VERSION 5.7 ;
  NOWIREEXTENSIONATPIN ON ;
  DIVIDERCHAR "/" ;
  BUSBITCHARS "[]" ;
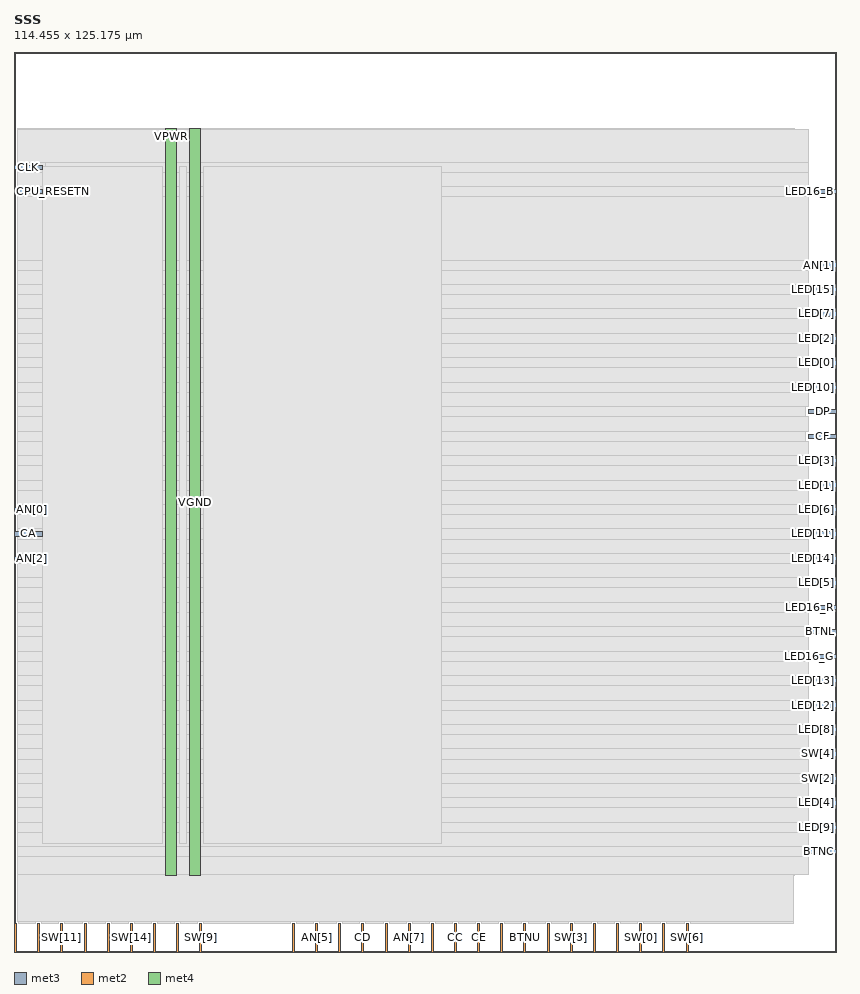
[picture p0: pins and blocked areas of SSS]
MACRO SSS
  CLASS BLOCK ;
  FOREIGN SSS ;
  ORIGIN 0.000 0.000 ;
  SIZE 114.455 BY 125.175 ;
  PIN AN[0]
    DIRECTION OUTPUT ;
    USE SIGNAL ;
    ANTENNADIFFAREA 0.445500 ;
    PORT
      LAYER met3 ;
        RECT 0.000 61.240 4.000 61.840 ;
    END
  END AN[0]
  PIN AN[1]
    DIRECTION OUTPUT ;
    USE SIGNAL ;
    ANTENNADIFFAREA 0.445500 ;
    PORT
      LAYER met3 ;
        RECT 110.455 95.240 114.455 95.840 ;
    END
  END AN[1]
  PIN AN[2]
    DIRECTION OUTPUT ;
    USE SIGNAL ;
    ANTENNADIFFAREA 0.445500 ;
    PORT
      LAYER met3 ;
        RECT 0.000 54.440 4.000 55.040 ;
    END
  END AN[2]
  PIN AN[3]
    DIRECTION OUTPUT ;
    USE SIGNAL ;
    ANTENNADIFFAREA 0.445500 ;
    PORT
      LAYER met2 ;
        RECT 67.710 0.000 67.990 4.000 ;
    END
  END AN[3]
  PIN AN[4]
    DIRECTION OUTPUT ;
    USE SIGNAL ;
    ANTENNADIFFAREA 0.445500 ;
    PORT
      LAYER met2 ;
        RECT 38.730 0.000 39.010 4.000 ;
    END
  END AN[4]
  PIN AN[5]
    DIRECTION OUTPUT ;
    USE SIGNAL ;
    ANTENNADIFFAREA 0.445500 ;
    PORT
      LAYER met2 ;
        RECT 41.950 0.000 42.230 4.000 ;
    END
  END AN[5]
  PIN AN[6]
    DIRECTION OUTPUT ;
    USE SIGNAL ;
    ANTENNADIFFAREA 0.445500 ;
    PORT
      LAYER met2 ;
        RECT 45.170 0.000 45.450 4.000 ;
    END
  END AN[6]
  PIN AN[7]
    DIRECTION OUTPUT ;
    USE SIGNAL ;
    ANTENNADIFFAREA 0.445500 ;
    PORT
      LAYER met2 ;
        RECT 54.830 0.000 55.110 4.000 ;
    END
  END AN[7]
  PIN BTNC
    DIRECTION INPUT ;
    USE SIGNAL ;
    ANTENNAGATEAREA 0.126000 ;
    PORT
      LAYER met3 ;
        RECT 110.455 13.640 114.455 14.240 ;
    END
  END BTNC
  PIN BTND
    DIRECTION INPUT ;
    USE SIGNAL ;
    PORT
      LAYER met2 ;
        RECT 0.090 0.000 0.370 4.000 ;
    END
  END BTND
  PIN BTNL
    DIRECTION INPUT ;
    USE SIGNAL ;
    ANTENNAGATEAREA 0.196500 ;
    PORT
      LAYER met3 ;
        RECT 110.455 44.240 114.455 44.840 ;
    END
  END BTNL
  PIN BTNR
    DIRECTION INPUT ;
    USE SIGNAL ;
    ANTENNAGATEAREA 0.196500 ;
    PORT
      LAYER met2 ;
        RECT 74.150 0.000 74.430 4.000 ;
    END
  END BTNR
  PIN BTNU
    DIRECTION INPUT ;
    USE SIGNAL ;
    ANTENNAGATEAREA 0.196500 ;
    PORT
      LAYER met2 ;
        RECT 70.930 0.000 71.210 4.000 ;
    END
  END BTNU
  PIN CA
    DIRECTION OUTPUT ;
    USE SIGNAL ;
    ANTENNADIFFAREA 0.445500 ;
    PORT
      LAYER met3 ;
        RECT 0.000 57.840 4.000 58.440 ;
    END
  END CA
  PIN CB
    DIRECTION OUTPUT ;
    USE SIGNAL ;
    ANTENNADIFFAREA 0.445500 ;
    PORT
      LAYER met2 ;
        RECT 58.050 0.000 58.330 4.000 ;
    END
  END CB
  PIN CC
    DIRECTION OUTPUT ;
    USE SIGNAL ;
    ANTENNADIFFAREA 0.445500 ;
    PORT
      LAYER met2 ;
        RECT 61.270 0.000 61.550 4.000 ;
    END
  END CC
  PIN CD
    DIRECTION OUTPUT ;
    USE SIGNAL ;
    ANTENNADIFFAREA 0.445500 ;
    PORT
      LAYER met2 ;
        RECT 48.390 0.000 48.670 4.000 ;
    END
  END CD
  PIN CE
    DIRECTION OUTPUT ;
    USE SIGNAL ;
    ANTENNADIFFAREA 0.445500 ;
    PORT
      LAYER met2 ;
        RECT 64.490 0.000 64.770 4.000 ;
    END
  END CE
  PIN CF
    DIRECTION OUTPUT ;
    USE SIGNAL ;
    ANTENNADIFFAREA 0.445500 ;
    PORT
      LAYER met3 ;
        RECT 110.455 71.440 114.455 72.040 ;
    END
  END CF
  PIN CG
    DIRECTION OUTPUT ;
    USE SIGNAL ;
    ANTENNADIFFAREA 0.445500 ;
    PORT
      LAYER met2 ;
        RECT 51.610 0.000 51.890 4.000 ;
    END
  END CG
  PIN CLK
    DIRECTION INPUT ;
    USE SIGNAL ;
    ANTENNAGATEAREA 0.852000 ;
    PORT
      LAYER met3 ;
        RECT 0.000 108.840 4.000 109.440 ;
    END
  END CLK
  PIN CPU_RESETN
    DIRECTION INPUT ;
    USE SIGNAL ;
    ANTENNAGATEAREA 0.196500 ;
    PORT
      LAYER met3 ;
        RECT 0.000 105.440 4.000 106.040 ;
    END
  END CPU_RESETN
  PIN DP
    DIRECTION OUTPUT ;
    USE SIGNAL ;
    PORT
      LAYER met3 ;
        RECT 110.455 74.840 114.455 75.440 ;
    END
  END DP
  PIN LED16_B
    DIRECTION OUTPUT ;
    USE SIGNAL ;
    PORT
      LAYER met3 ;
        RECT 110.455 105.440 114.455 106.040 ;
    END
  END LED16_B
  PIN LED16_G
    DIRECTION OUTPUT ;
    USE SIGNAL ;
    ANTENNADIFFAREA 0.445500 ;
    PORT
      LAYER met3 ;
        RECT 110.455 40.840 114.455 41.440 ;
    END
  END LED16_G
  PIN LED16_R
    DIRECTION OUTPUT ;
    USE SIGNAL ;
    ANTENNADIFFAREA 0.445500 ;
    PORT
      LAYER met3 ;
        RECT 110.455 47.640 114.455 48.240 ;
    END
  END LED16_R
  PIN LED[0]
    DIRECTION OUTPUT ;
    USE SIGNAL ;
    ANTENNADIFFAREA 0.445500 ;
    PORT
      LAYER met3 ;
        RECT 110.455 81.640 114.455 82.240 ;
    END
  END LED[0]
  PIN LED[10]
    DIRECTION OUTPUT ;
    USE SIGNAL ;
    ANTENNADIFFAREA 0.445500 ;
    PORT
      LAYER met3 ;
        RECT 110.455 78.240 114.455 78.840 ;
    END
  END LED[10]
  PIN LED[11]
    DIRECTION OUTPUT ;
    USE SIGNAL ;
    ANTENNADIFFAREA 0.445500 ;
    PORT
      LAYER met3 ;
        RECT 110.455 57.840 114.455 58.440 ;
    END
  END LED[11]
  PIN LED[12]
    DIRECTION OUTPUT ;
    USE SIGNAL ;
    ANTENNADIFFAREA 0.445500 ;
    PORT
      LAYER met3 ;
        RECT 110.455 34.040 114.455 34.640 ;
    END
  END LED[12]
  PIN LED[13]
    DIRECTION OUTPUT ;
    USE SIGNAL ;
    ANTENNADIFFAREA 0.445500 ;
    PORT
      LAYER met3 ;
        RECT 110.455 37.440 114.455 38.040 ;
    END
  END LED[13]
  PIN LED[14]
    DIRECTION OUTPUT ;
    USE SIGNAL ;
    ANTENNADIFFAREA 0.445500 ;
    PORT
      LAYER met3 ;
        RECT 110.455 54.440 114.455 55.040 ;
    END
  END LED[14]
  PIN LED[15]
    DIRECTION OUTPUT ;
    USE SIGNAL ;
    ANTENNADIFFAREA 0.445500 ;
    PORT
      LAYER met3 ;
        RECT 110.455 91.840 114.455 92.440 ;
    END
  END LED[15]
  PIN LED[1]
    DIRECTION OUTPUT ;
    USE SIGNAL ;
    ANTENNADIFFAREA 0.445500 ;
    PORT
      LAYER met3 ;
        RECT 110.455 64.640 114.455 65.240 ;
    END
  END LED[1]
  PIN LED[2]
    DIRECTION OUTPUT ;
    USE SIGNAL ;
    ANTENNADIFFAREA 0.445500 ;
    PORT
      LAYER met3 ;
        RECT 110.455 85.040 114.455 85.640 ;
    END
  END LED[2]
  PIN LED[3]
    DIRECTION OUTPUT ;
    USE SIGNAL ;
    ANTENNADIFFAREA 0.445500 ;
    PORT
      LAYER met3 ;
        RECT 110.455 68.040 114.455 68.640 ;
    END
  END LED[3]
  PIN LED[4]
    DIRECTION OUTPUT ;
    USE SIGNAL ;
    ANTENNADIFFAREA 0.445500 ;
    PORT
      LAYER met3 ;
        RECT 110.455 20.440 114.455 21.040 ;
    END
  END LED[4]
  PIN LED[5]
    DIRECTION OUTPUT ;
    USE SIGNAL ;
    ANTENNADIFFAREA 0.445500 ;
    PORT
      LAYER met3 ;
        RECT 110.455 51.040 114.455 51.640 ;
    END
  END LED[5]
  PIN LED[6]
    DIRECTION OUTPUT ;
    USE SIGNAL ;
    ANTENNADIFFAREA 0.445500 ;
    PORT
      LAYER met3 ;
        RECT 110.455 61.240 114.455 61.840 ;
    END
  END LED[6]
  PIN LED[7]
    DIRECTION OUTPUT ;
    USE SIGNAL ;
    ANTENNADIFFAREA 0.445500 ;
    PORT
      LAYER met3 ;
        RECT 110.455 88.440 114.455 89.040 ;
    END
  END LED[7]
  PIN LED[8]
    DIRECTION OUTPUT ;
    USE SIGNAL ;
    ANTENNADIFFAREA 0.445500 ;
    PORT
      LAYER met3 ;
        RECT 110.455 30.640 114.455 31.240 ;
    END
  END LED[8]
  PIN LED[9]
    DIRECTION OUTPUT ;
    USE SIGNAL ;
    ANTENNADIFFAREA 0.445500 ;
    PORT
      LAYER met3 ;
        RECT 110.455 17.040 114.455 17.640 ;
    END
  END LED[9]
  PIN SW[0]
    DIRECTION INPUT ;
    USE SIGNAL ;
    ANTENNAGATEAREA 0.196500 ;
    PORT
      LAYER met2 ;
        RECT 87.030 0.000 87.310 4.000 ;
    END
  END SW[0]
  PIN SW[10]
    DIRECTION INPUT ;
    USE SIGNAL ;
    PORT
      LAYER met2 ;
        RECT 3.310 0.000 3.590 4.000 ;
    END
  END SW[10]
  PIN SW[11]
    DIRECTION INPUT ;
    USE SIGNAL ;
    PORT
      LAYER met2 ;
        RECT 6.530 0.000 6.810 4.000 ;
    END
  END SW[11]
  PIN SW[12]
    DIRECTION INPUT ;
    USE SIGNAL ;
    PORT
      LAYER met2 ;
        RECT 9.750 0.000 10.030 4.000 ;
    END
  END SW[12]
  PIN SW[13]
    DIRECTION INPUT ;
    USE SIGNAL ;
    PORT
      LAYER met2 ;
        RECT 12.970 0.000 13.250 4.000 ;
    END
  END SW[13]
  PIN SW[14]
    DIRECTION INPUT ;
    USE SIGNAL ;
    PORT
      LAYER met2 ;
        RECT 16.190 0.000 16.470 4.000 ;
    END
  END SW[14]
  PIN SW[15]
    DIRECTION INPUT ;
    USE SIGNAL ;
    PORT
      LAYER met2 ;
        RECT 19.410 0.000 19.690 4.000 ;
    END
  END SW[15]
  PIN SW[1]
    DIRECTION INPUT ;
    USE SIGNAL ;
    ANTENNAGATEAREA 0.196500 ;
    PORT
      LAYER met2 ;
        RECT 90.250 0.000 90.530 4.000 ;
    END
  END SW[1]
  PIN SW[2]
    DIRECTION INPUT ;
    USE SIGNAL ;
    ANTENNAGATEAREA 0.196500 ;
    PORT
      LAYER met3 ;
        RECT 110.455 23.840 114.455 24.440 ;
    END
  END SW[2]
  PIN SW[3]
    DIRECTION INPUT ;
    USE SIGNAL ;
    ANTENNAGATEAREA 0.196500 ;
    PORT
      LAYER met2 ;
        RECT 77.370 0.000 77.650 4.000 ;
    END
  END SW[3]
  PIN SW[4]
    DIRECTION INPUT ;
    USE SIGNAL ;
    ANTENNAGATEAREA 0.196500 ;
    PORT
      LAYER met3 ;
        RECT 110.455 27.240 114.455 27.840 ;
    END
  END SW[4]
  PIN SW[5]
    DIRECTION INPUT ;
    USE SIGNAL ;
    ANTENNAGATEAREA 0.196500 ;
    PORT
      LAYER met2 ;
        RECT 80.590 0.000 80.870 4.000 ;
    END
  END SW[5]
  PIN SW[6]
    DIRECTION INPUT ;
    USE SIGNAL ;
    ANTENNAGATEAREA 0.196500 ;
    PORT
      LAYER met2 ;
        RECT 93.470 0.000 93.750 4.000 ;
    END
  END SW[6]
  PIN SW[7]
    DIRECTION INPUT ;
    USE SIGNAL ;
    ANTENNAGATEAREA 0.196500 ;
    PORT
      LAYER met2 ;
        RECT 83.810 0.000 84.090 4.000 ;
    END
  END SW[7]
  PIN SW[8]
    DIRECTION INPUT ;
    USE SIGNAL ;
    PORT
      LAYER met2 ;
        RECT 22.630 0.000 22.910 4.000 ;
    END
  END SW[8]
  PIN SW[9]
    DIRECTION INPUT ;
    USE SIGNAL ;
    PORT
      LAYER met2 ;
        RECT 25.850 0.000 26.130 4.000 ;
    END
  END SW[9]
  PIN VGND
    DIRECTION INOUT ;
    USE GROUND ;
    PORT
      LAYER met4 ;
        RECT 24.340 10.640 25.940 114.480 ;
    END
  END VGND
  PIN VPWR
    DIRECTION INOUT ;
    USE POWER ;
    PORT
      LAYER met4 ;
        RECT 21.040 10.640 22.640 114.480 ;
    END
  END VPWR
  OBS
      LAYER nwell ;
        RECT 5.330 10.795 108.750 114.325 ;
      LAYER li1 ;
        RECT 5.520 10.795 108.560 114.325 ;
      LAYER met1 ;
        RECT 0.530 10.640 108.560 114.480 ;
      LAYER met2 ;
        RECT 0.550 4.280 108.460 114.425 ;
        RECT 0.650 4.000 3.030 4.280 ;
        RECT 3.870 4.000 6.250 4.280 ;
        RECT 7.090 4.000 9.470 4.280 ;
        RECT 10.310 4.000 12.690 4.280 ;
        RECT 13.530 4.000 15.910 4.280 ;
        RECT 16.750 4.000 19.130 4.280 ;
        RECT 19.970 4.000 22.350 4.280 ;
        RECT 23.190 4.000 25.570 4.280 ;
        RECT 26.410 4.000 38.450 4.280 ;
        RECT 39.290 4.000 41.670 4.280 ;
        RECT 42.510 4.000 44.890 4.280 ;
        RECT 45.730 4.000 48.110 4.280 ;
        RECT 48.950 4.000 51.330 4.280 ;
        RECT 52.170 4.000 54.550 4.280 ;
        RECT 55.390 4.000 57.770 4.280 ;
        RECT 58.610 4.000 60.990 4.280 ;
        RECT 61.830 4.000 64.210 4.280 ;
        RECT 65.050 4.000 67.430 4.280 ;
        RECT 68.270 4.000 70.650 4.280 ;
        RECT 71.490 4.000 73.870 4.280 ;
        RECT 74.710 4.000 77.090 4.280 ;
        RECT 77.930 4.000 80.310 4.280 ;
        RECT 81.150 4.000 83.530 4.280 ;
        RECT 84.370 4.000 86.750 4.280 ;
        RECT 87.590 4.000 89.970 4.280 ;
        RECT 90.810 4.000 93.190 4.280 ;
        RECT 94.030 4.000 108.460 4.280 ;
      LAYER met3 ;
        RECT 0.525 109.840 110.455 114.405 ;
        RECT 4.400 108.440 110.455 109.840 ;
        RECT 0.525 106.440 110.455 108.440 ;
        RECT 4.400 105.040 110.055 106.440 ;
        RECT 0.525 96.240 110.455 105.040 ;
        RECT 0.525 94.840 110.055 96.240 ;
        RECT 0.525 92.840 110.455 94.840 ;
        RECT 0.525 91.440 110.055 92.840 ;
        RECT 0.525 89.440 110.455 91.440 ;
        RECT 0.525 88.040 110.055 89.440 ;
        RECT 0.525 86.040 110.455 88.040 ;
        RECT 0.525 84.640 110.055 86.040 ;
        RECT 0.525 82.640 110.455 84.640 ;
        RECT 0.525 81.240 110.055 82.640 ;
        RECT 0.525 79.240 110.455 81.240 ;
        RECT 0.525 77.840 110.055 79.240 ;
        RECT 0.525 75.840 110.455 77.840 ;
        RECT 0.525 74.440 110.055 75.840 ;
        RECT 0.525 72.440 110.455 74.440 ;
        RECT 0.525 71.040 110.055 72.440 ;
        RECT 0.525 69.040 110.455 71.040 ;
        RECT 0.525 67.640 110.055 69.040 ;
        RECT 0.525 65.640 110.455 67.640 ;
        RECT 0.525 64.240 110.055 65.640 ;
        RECT 0.525 62.240 110.455 64.240 ;
        RECT 4.400 60.840 110.055 62.240 ;
        RECT 0.525 58.840 110.455 60.840 ;
        RECT 4.400 57.440 110.055 58.840 ;
        RECT 0.525 55.440 110.455 57.440 ;
        RECT 4.400 54.040 110.055 55.440 ;
        RECT 0.525 52.040 110.455 54.040 ;
        RECT 0.525 50.640 110.055 52.040 ;
        RECT 0.525 48.640 110.455 50.640 ;
        RECT 0.525 47.240 110.055 48.640 ;
        RECT 0.525 45.240 110.455 47.240 ;
        RECT 0.525 43.840 110.055 45.240 ;
        RECT 0.525 41.840 110.455 43.840 ;
        RECT 0.525 40.440 110.055 41.840 ;
        RECT 0.525 38.440 110.455 40.440 ;
        RECT 0.525 37.040 110.055 38.440 ;
        RECT 0.525 35.040 110.455 37.040 ;
        RECT 0.525 33.640 110.055 35.040 ;
        RECT 0.525 31.640 110.455 33.640 ;
        RECT 0.525 30.240 110.055 31.640 ;
        RECT 0.525 28.240 110.455 30.240 ;
        RECT 0.525 26.840 110.055 28.240 ;
        RECT 0.525 24.840 110.455 26.840 ;
        RECT 0.525 23.440 110.055 24.840 ;
        RECT 0.525 21.440 110.455 23.440 ;
        RECT 0.525 20.040 110.055 21.440 ;
        RECT 0.525 18.040 110.455 20.040 ;
        RECT 0.525 16.640 110.055 18.040 ;
        RECT 0.525 14.640 110.455 16.640 ;
        RECT 0.525 13.240 110.055 14.640 ;
        RECT 0.525 10.715 110.455 13.240 ;
      LAYER met4 ;
        RECT 3.975 15.135 20.640 109.305 ;
        RECT 23.040 15.135 23.940 109.305 ;
        RECT 26.340 15.135 59.505 109.305 ;
  END
END SSS
END LIBRARY

